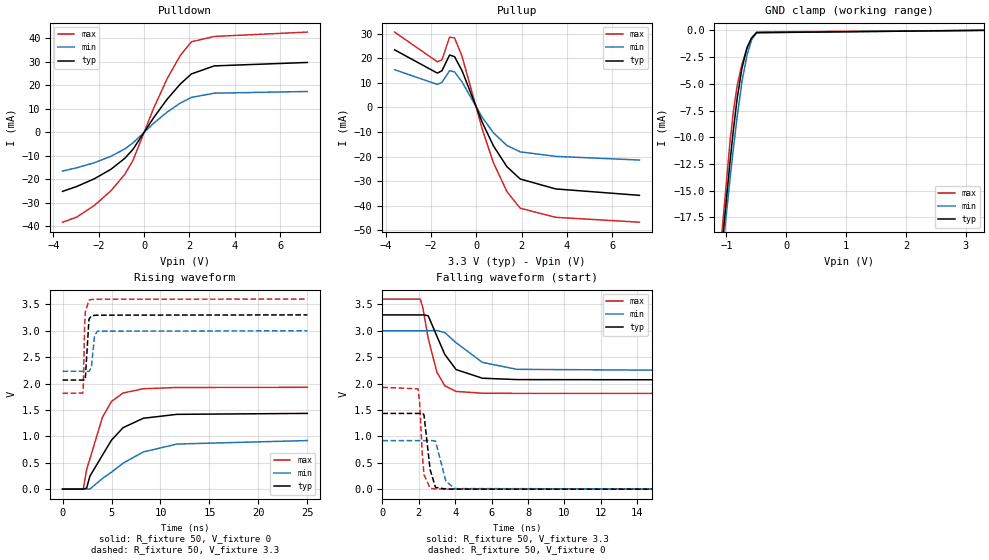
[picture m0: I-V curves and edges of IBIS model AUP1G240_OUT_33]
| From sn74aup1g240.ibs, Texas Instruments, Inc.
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[Model]   AUP1G240_OUT_33
Model_type  3-state
Enable   Active-Low
Vref =   0
Rref =   1E6
Cref =   30p
Vmeas =   1.65
| variable   typ   min   max
C_comp   2.07pF   1.81pF   2.41pF
| C_pullup   3.15pF   1.95pF   4.02pF
| C_pulldown   2.43pF   2.23pF   2.95pF
| C_tri-state   2.07pF   1.81pF   2.41pF
[Temperature Range]   40   100   -40
| Ambient temperature   25   85   -40
[Voltage range]   3.3   3   3.6
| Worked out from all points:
|   slope of the pulldown table from 0 to 0.495 V, typ, clamps not added: 68.4 ohm
|   slope of the pullup table from 0 to 0.495 V, typ, clamps not added: 45.7 ohm
|   GND clamp passes 1 mA (typ) near -0.61 V on its own axis
|   rising waveform, R_fixture 50, V_fixture 0: 20-80 % time 3.15ns typ, 4.82ns min, 2.07ns max; typ from 0 V to 1.43 V
|   falling waveform, R_fixture 50, V_fixture 3.3: 20-80 % time 1.07ns typ, 1.77ns min, 721ps max; typ from 3.3 V to 2.07 V
|   rising waveform, R_fixture 50, V_fixture 3.3: 20-80 % time 155ps typ, 217ps min, 131ps max; typ from 2.07 V to 3.3 V
|   falling waveform, R_fixture 50, V_fixture 0: 20-80 % time 244ps typ, 345ps min, 189ps max; typ from 1.43 V to 0 V
[GND Clamp]
| AUP1G240_OUT_33
|   Voltage   I(typ)   I(min)   I(max)
-3.6V     -193.5mA   -179.8mA   -210.3mA
-1.125V   -23.21mA   -23.99mA   -22.31mA
-1.1V     -21.68mA   -22.59mA   -20.6mA
-1.075V   -20.16mA   -21.2mA    -18.91mA
-940mV    -12.31mA   -13.93mA   -10.42mA
-885mV    -9.392mA   -11.14mA   -7.651mA
-820mV    -6.352mA   -8.056mA   -5.152mA
-740mV    -3.533mA   -4.797mA   -3.135mA
-655mV    -1.602mA   -2.3mA     -1.69mA
-580mV    -733.4uA   -905.1uA   -734uA
-495mV    -220.6uA   -215.1uA   -155.7uA
3.3V      272.7pA    1.972nA    65.76pA
[Pulldown]
| AUP1G240_OUT_33
|   Voltage   I(typ)   I(min)   I(max)
-3.6V     -25.22mA   -16.54mA   -38.34mA
-2.985V   -23.17mA   -15.19mA   -36.23mA
-2.205V   -19.89mA   -13.04mA   -31.29mA
-1.46V    -15.76mA   -10.26mA   -24.93mA
-855mV    -11.15mA   -7.128mA   -17.97mA
-490mV    -7.269mA   -4.538mA   -11.95mA
415mV     6.109mA    3.748mA    10.09mA
1.015V    14.06mA    8.579mA    22.82mA
1.6V      20.58mA    12.45mA    32.78mA
2.085V    24.83mA    14.83mA    38.52mA
3.09V     28.26mA    16.63mA    40.81mA
7.2V      29.73mA    17.36mA    42.67mA
[Pullup]
| AUP1G240_OUT_33
|   Voltage   I(typ)   I(min)   I(max)
-3.6V     23.4mA     15.31mA    30.62mA
-1.715V   13.93mA    9.327mA    18.54mA
-1.51V    14.91mA    10.2mA     19.34mA
-1.175V   21.28mA    14.91mA    28.58mA
-955mV    20.62mA    14.4mA     28.23mA
-625mV    14.91mA    10.34mA    20.78mA
270mV     -6.183mA   -4.136mA   -9mA
765mV     -15.76mA   -10.39mA   -22.64mA
1.355V    -24.14mA   -15.52mA   -34.29mA
1.94V     -29.14mA   -18.1mA    -41.04mA
3.505V    -33.19mA   -19.94mA   -44.73mA
7.2V      -35.8mA    -21.44mA   -46.72mA
[Ramp]
| AUP1G240_OUT_33
| variable   typ   min   max
dV/dt_r   0.86/3.15E-09   0.55/4.84E-09   1.16/2.07E-09
dV/dt_f   0.75/1.08E-09   0.47/1.78E-09   1.08/7.24E-10
R_load = 50
[Rising Waveform]
| AUP1G240_OUT_33
R_fixture =   50
C_fixture =   0
L_fixture =   0
V_fixture =   0
V_fixture_min = 0
V_fixture_max = 0
|   Time   V(typ)   V(min)   V(max)
0s        12.11nV    31.97nV    1.283nV
2.12ns    160.7uV    -11.23uV   -1.498mV
2.46ns    17.83mV    142.5uV    371.8mV
2.79ns    243mV      357.5uV    569mV
4.08ns    644.3mV    201.4mV    1.363V
5ns       927.7mV    319.8mV    1.661V
6.185ns   1.164V     491.3mV    1.821V
8.25ns    1.342V     703.7mV    1.901V
11.68ns   1.416V     853.6mV    1.925V
24.99ns   1.434V     919.3mV    1.928V
[Falling Waveform]
| AUP1G240_OUT_33
R_fixture =   50
C_fixture =   0
L_fixture =   0
V_fixture =   3.3
V_fixture_min = 3
V_fixture_max = 3.6
|   Time   V(typ)   V(min)   V(max)
0s        3.3V       3V         3.6V
2.085ns   3.3V       3V         3.6V
2.23ns    3.3V       3V         3.425V
2.515ns   3.286V     3V         2.861V
2.995ns   2.897V     3.004V     2.213V
3.43ns    2.551V     2.965V     1.958V
4.05ns    2.264V     2.772V     1.851V
5.495ns   2.101V     2.401V     1.817V
7.395ns   2.075V     2.269V     1.814V
24.99ns   2.067V     2.233V     1.814V
[Rising Waveform]
| AUP1G240_OUT_33
R_fixture =   50
C_fixture =   0
L_fixture =   0
V_fixture =   3.3
V_fixture_min = 3
V_fixture_max = 3.6
|   Time   V(typ)   V(min)   V(max)
0s        2.066V     2.232V     1.814V
2.065ns   2.066V     2.232V     1.82V
2.13ns    2.066V     2.232V     1.972V
2.245ns   2.066V     2.232V     2.998V
2.32ns    2.075V     2.232V     3.352V
2.7ns     3.217V     2.229V     3.581V
2.945ns   3.282V     2.3V       3.591V
3.27ns    3.291V     2.908V     3.596V
3.57ns    3.295V     2.991V     3.597V
24.99ns   3.3V       3V         3.6V
[Falling Waveform]
| AUP1G240_OUT_33
R_fixture =   50
C_fixture =   0
L_fixture =   0
V_fixture =   0
V_fixture_min = 0
V_fixture_max = 0
|   Time   V(typ)   V(min)   V(max)
0s        1.434V     920.1mV    1.928V
1.955ns   1.434V     920mV      1.901V
2.04ns    1.435V     920mV      1.679V
2.195ns   1.439V     919.7mV    652.9mV
2.285ns   1.408V     919.7mV    277.9mV
2.625ns   367.3mV    924mV      15.16mV
2.92ns    32.66mV    909.6mV    4.237mV
3.485ns   3.52mV     152.2mV    822.1uV
3.98ns    1.124mV    10.98mV    248.8uV
24.99ns   26.42nV    83.74nV    6.095nV
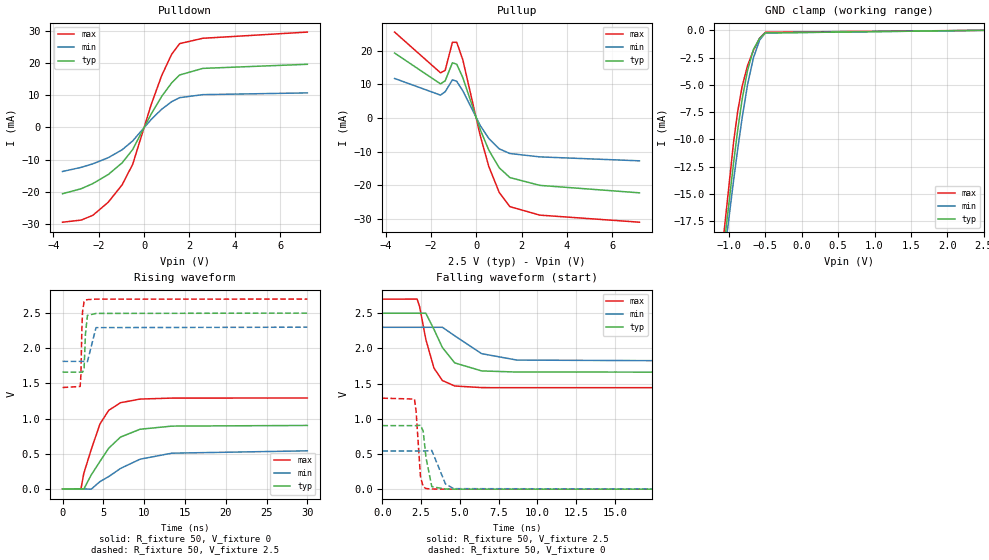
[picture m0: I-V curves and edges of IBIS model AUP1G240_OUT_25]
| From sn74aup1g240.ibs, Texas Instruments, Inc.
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[Model]   AUP1G240_OUT_25
Model_type  3-state
Enable   Active-Low
Vref =   0
Rref =   1E6
Cref =   30p
Vmeas =   1.25
| variable   typ   min   max
C_comp   2.12pF   1.87pF   2.42pF
| C_pullup   3.16pF   2.01pF   4.05pF
| C_pulldown   2.52pF   2.24pF   3.06pF
| C_tri-state   2.12pF   1.87pF   2.42pF
[Temperature Range]   40   100   -40
| Ambient temperature   25   85   -40
[Voltage range]   2.5   2.3   2.7
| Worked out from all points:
|   slope of the pulldown table from 0 to 0.375 V, typ, clamps not added: 75.2 ohm
|   slope of the pullup table from 0 to 0.375 V, typ, clamps not added: 55.1 ohm
|   GND clamp passes 1 mA (typ) near -0.61 V on its own axis
|   rising waveform, R_fixture 50, V_fixture 0: 20-80 % time 3.54ns typ, 5.12ns min, 2.39ns max; typ from 0 V to 0.903 V
|   falling waveform, R_fixture 50, V_fixture 2.5: 20-80 % time 1.27ns typ, 2.05ns min, 857ps max; typ from 2.5 V to 1.66 V
|   rising waveform, R_fixture 50, V_fixture 2.5: 20-80 % time 175ps typ, 253ps min, 147ps max; typ from 1.66 V to 2.5 V
|   falling waveform, R_fixture 50, V_fixture 0: 20-80 % time 273ps typ, 387ps min, 217ps max; typ from 0.903 V to 0 V
[GND Clamp]
| AUP1G240_OUT_25
|   Voltage   I(typ)   I(min)   I(max)
-3.6V     -193.5mA   -179.8mA   -210.3mA
-1.13V    -23.52mA   -24.27mA   -22.66mA
-1.105V   -21.99mA   -22.87mA   -20.94mA
-1.08V    -20.47mA   -21.48mA   -19.25mA
-935mV    -12.04mA   -13.67mA   -10.14mA
-880mV    -9.14mA    -10.89mA   -7.431mA
-820mV    -6.352mA   -8.056mA   -5.152mA
-745mV    -3.68mA    -4.977mA   -3.233mA
-665mV    -1.77mA    -2.542mA   -1.842mA
-580mV    -733.4uA   -905.1uA   -734uA
-500mV    -240.6uA   -235.8uA   -174.4uA
2.5V      210.4pA    1.91nA     47.26pA
[Pulldown]
| AUP1G240_OUT_25
|   Voltage   I(typ)   I(min)   I(max)
-3.6V     -20.57mA   -13.67mA   -29.41mA
-2.78V    -19.03mA   -12.39mA   -28.76mA
-2.265V   -17.43mA   -11.3mA    -27.29mA
-1.58V    -14.6mA    -9.373mA   -23.19mA
-970mV    -10.98mA   -6.922mA   -17.8mA
-505mV    -6.845mA   -4.179mA   -11.45mA
310mV     4.162mA    2.467mA    7.071mA
775mV     9.655mA    5.67mA     16.13mA
1.215V    13.84mA    8.012mA    22.73mA
1.565V    16.29mA    9.252mA    26.03mA
2.59V     18.34mA    10.19mA    27.69mA
7.2V      19.61mA    10.73mA    29.61mA
[Pullup]
| AUP1G240_OUT_25
|   Voltage   I(typ)   I(min)   I(max)
-3.6V     19.35mA    11.79mA    25.58mA
-1.575V   10.18mA    6.835mA    13.47mA
-1.37V    11.08mA    7.836mA    14.2mA
-1.05V    16.45mA    11.37mA    22.53mA
-860mV    16.03mA    10.95mA    22.55mA
-590mV    12.03mA    8.106mA    17.31mA
180mV     -3.459mA   -2.233mA   -5.283mA
555mV     -9.511mA   -6.049mA   -14.36mA
1.015V    -14.77mA   -9.13mA    -22.1mA
1.485V    -17.68mA   -10.53mA   -26.32mA
2.805V    -20mA      -11.53mA   -28.85mA
7.2V      -22.22mA   -12.7mA    -30.95mA
[Ramp]
| AUP1G240_OUT_25
| variable   typ   min   max
dV/dt_r   0.54/3.56E-09   0.33/5.17E-09   0.78/2.39E-09
dV/dt_f   0.51/1.27E-09   0.30/2.06E-09   0.76/8.61E-10
R_load = 50
[Rising Waveform]
| AUP1G240_OUT_25
R_fixture =   50
C_fixture =   0
L_fixture =   0
V_fixture =   0
V_fixture_min = 0
V_fixture_max = 0
|   Time   V(typ)   V(min)   V(max)
0s        8.96nV     28.07nV    865.3pV
2.265ns   58.37uV    -8.263uV   1.77mV
2.605ns   -2.543mV   -1.172uV   222.1mV
3.515ns   198.6mV    -3.157mV   559.5mV
4.585ns   391mV      104.2mV    923.9mV
5.665ns   580mV      176.4mV    1.118V
7.1ns     737.4mV    291.3mV    1.226V
9.5ns     848.9mV    423.2mV    1.278V
13.39ns   893.5mV    508.6mV    1.292V
29.99ns   902.9mV    541.9mV    1.293V
[Falling Waveform]
| AUP1G240_OUT_25
R_fixture =   50
C_fixture =   0
L_fixture =   0
V_fixture =   2.5
V_fixture_min = 2.3
V_fixture_max = 2.7
|   Time   V(typ)   V(min)   V(max)
0s        2.5V       2.3V       2.7V
2.24ns    2.5V       2.3V       2.701V
2.405ns   2.499V     2.3V       2.592V
2.805ns   2.499V     2.3V       2.128V
3.33ns    2.271V     2.3V       1.72V
3.875ns   2.012V     2.3V       1.543V
4.67ns    1.794V     2.179V     1.466V
6.41ns    1.68V      1.925V     1.443V
8.69ns    1.664V     1.834V     1.442V
29.99ns   1.662V     1.814V     1.442V
[Rising Waveform]
| AUP1G240_OUT_25
R_fixture =   50
C_fixture =   0
L_fixture =   0
V_fixture =   2.5
V_fixture_min = 2.3
V_fixture_max = 2.7
|   Time   V(typ)   V(min)   V(max)
0s        1.661V     1.814V     1.442V
2.16ns    1.661V     1.814V     1.457V
2.255ns   1.661V     1.814V     1.622V
2.37ns    1.66V      1.814V     2.273V
2.45ns    1.659V     1.814V     2.518V
2.64ns    1.703V     1.814V     2.662V
2.81ns    2.204V     1.814V     2.686V
3.05ns    2.467V     1.811V     2.692V
4.105ns   2.496V     2.294V     2.699V
29.99ns   2.5V       2.3V       2.7V
[Falling Waveform]
| AUP1G240_OUT_25
R_fixture =   50
C_fixture =   0
L_fixture =   0
V_fixture =   0
V_fixture_min = 0
V_fixture_max = 0
|   Time   V(typ)   V(min)   V(max)
0s        902.9mV    542.1mV    1.293V
2.07ns    902.6mV    542.1mV    1.28V
2.175ns   903mV      542mV      1.114V
2.46ns    908.1mV    541.7mV    174.9mV
2.635ns   825.7mV    541.7mV    34.71mV
2.815ns   447.7mV    542.5mV    8.342mV
3.19ns    35.55mV    550.1mV    2.449mV
4.07ns    1.667mV    75.73mV    264.9uV
4.6ns     593.9uV    7.206mV    91.14uV
29.99ns   35.6nV     66.32nV    6.812nV
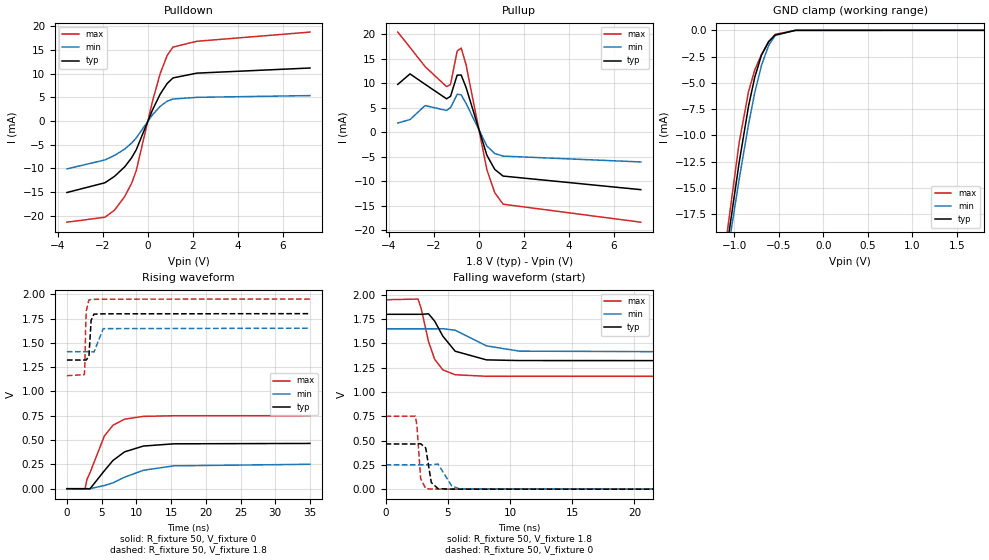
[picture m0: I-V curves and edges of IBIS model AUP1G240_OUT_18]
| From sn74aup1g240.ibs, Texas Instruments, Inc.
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[Model]   AUP1G240_OUT_18
Model_type  3-state
Enable   Active-Low
Vref =   0
Rref =   1E6
Cref =   30p
Vmeas =   0.9
| variable   typ   min   max
C_comp   2.18pF   1.95pF   2.43pF
| C_pullup   3.13pF   2.07pF   4.02pF
| C_pulldown   2.62pF   2.25pF   3.11pF
| C_tri-state   2.18pF   1.95pF   2.43pF
[Temperature Range]   40   100   -40
| Ambient temperature   25   85   -40
[Voltage range]   1.8   1.65   1.95
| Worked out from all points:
|   slope of the pulldown table from 0 to 0.27 V, typ, clamps not added: 88.7 ohm
|   slope of the pullup table from 0 to 0.27 V, typ, clamps not added: 73.8 ohm
|   GND clamp passes 1 mA (typ) near -0.61 V on its own axis
|   rising waveform, R_fixture 50, V_fixture 0: 20-80 % time 3.87ns typ, 5.45ns min, 2.72ns max; typ from 0 V to 0.465 V
|   falling waveform, R_fixture 50, V_fixture 1.8: 20-80 % time 1.55ns typ, 2.45ns min, 1.04ns max; typ from 1.8 V to 1.32 V
|   rising waveform, R_fixture 50, V_fixture 1.8: 20-80 % time 225ps typ, 296ps min, 160ps max; typ from 1.32 V to 1.8 V
|   falling waveform, R_fixture 50, V_fixture 0: 20-80 % time 323ps typ, 464ps min, 230ps max; typ from 0.465 V to 0 V
[GND Clamp]
| AUP1G240_OUT_18
|   Voltage   I(typ)   I(min)   I(max)
-3.6V     -193.5mA   -179.8mA   -210.3mA
-1.145V   -24.45mA   -25.12mA   -23.69mA
-1.12V    -22.91mA   -23.71mA   -21.97mA
-1.095V   -21.38mA   -22.31mA   -20.26mA
-945mV    -12.59mA   -14.19mA   -10.7mA
-840mV    -7.225mA   -8.974mA   -5.843mA
-770mV    -4.469mA   -5.928mA   -3.764mA
-695mV    -2.373mA   -3.346mA   -2.326mA
-615mV    -1.069mA   -1.463mA   -1.136mA
-540mV    -445.1uA   -477.4uA   -389.8uA
-315mV    -2.831uA   -4.163uA   -587.7nA
1.8V      163.6pA    2.099nA    32.78pA
[Pulldown]
| AUP1G240_OUT_18
|   Voltage   I(typ)   I(min)   I(max)
-3.6V     -15.12mA   -10.13mA   -21.39mA
-1.91V    -13.06mA   -8.236mA   -20.34mA
-1.485V   -11.71mA   -7.301mA   -18.84mA
-1.03V    -9.681mA   -5.933mA   -15.95mA
-725mV    -7.787mA   -4.683mA   -13.18mA
-520mV    -6.099mA   -3.59mA    -10.49mA
205mV     2.352mA    1.308mA    4.202mA
545mV     5.664mA    3.086mA    10.01mA
855mV     7.912mA    4.18mA     13.84mA
1.115V    9.087mA    4.628mA    15.61mA
2.18V     10.1mA     4.986mA    16.83mA
7.2V      11.18mA    5.355mA    18.77mA
[Pullup]
| AUP1G240_OUT_18
|   Voltage   I(typ)   I(min)   I(max)
-3.6V     9.764mA    1.888mA    20.42mA
-3.055V   11.9mA     2.599mA    17.29mA
-2.385V   9.785mA    5.444mA    13.38mA
-1.43V    6.82mA     4.441mA    9.299mA
-1.255V   7.335mA    5.04mA     9.735mA
-960mV    11.65mA    7.76mA     16.56mA
-780mV    11.66mA    7.635mA    17.16mA
-565mV    9.148mA    5.886mA    13.78mA
360mV     -4.671mA   -2.782mA   -7.616mA
710mV     -7.556mA   -4.323mA   -12.3mA
1.08V     -8.919mA   -4.855mA   -14.65mA
7.2V      -11.69mA   -6.041mA   -18.32mA
[Ramp]
| AUP1G240_OUT_18
| variable   typ   min   max
dV/dt_r   0.28/3.91E-09   0.15/5.57E-09   0.45/2.74E-09
dV/dt_f   0.29/1.56E-09   0.15/2.47E-09   0.48/1.04E-09
R_load = 50
[Rising Waveform]
| AUP1G240_OUT_18
R_fixture =   50
C_fixture =   0
L_fixture =   0
V_fixture =   0
V_fixture_min = 0
V_fixture_max = 0
|   Time   V(typ)   V(min)   V(max)
0s        6.973nV    25.31nV    613.1pV
2.6ns     2.172uV    -5.915uV   -4.821mV
2.89ns    390.8uV    -12.12uV   96.14mV
3.305ns   -2.687mV   5.918uV    161.3mV
5.385ns   184.2mV    32.48mV    541.1mV
6.64ns    290.8mV    60.66mV    653mV
8.3ns     378.8mV    118.1mV    714.9mV
11ns      438.6mV    189.3mV    743.5mV
15.4ns    461.5mV    235.1mV    750.3mV
34.99ns   465.4mV    251mV      750.9mV
[Falling Waveform]
| AUP1G240_OUT_18
R_fixture =   50
C_fixture =   0
L_fixture =   0
V_fixture =   1.8
V_fixture_min = 1.65
V_fixture_max = 1.95
|   Time   V(typ)   V(min)   V(max)
0s        1.8V       1.65V      1.95V
2.605ns   1.8V       1.65V      1.957V
2.85ns    1.8V       1.65V      1.864V
3.45ns    1.805V     1.65V      1.519V
3.94ns    1.73V      1.65V      1.337V
4.6ns     1.575V     1.652V     1.228V
5.59ns    1.42V      1.636V     1.178V
8.105ns   1.331V     1.475V     1.162V
10.74ns   1.324V     1.421V     1.162V
34.99ns   1.323V     1.409V     1.162V
[Rising Waveform]
| AUP1G240_OUT_18
R_fixture =   50
C_fixture =   0
L_fixture =   0
V_fixture =   1.8
V_fixture_min = 1.65
V_fixture_max = 1.95
|   Time   V(typ)   V(min)   V(max)
0s        1.323V     1.409V     1.162V
2.5ns     1.323V     1.409V     1.173V
2.575ns   1.323V     1.409V     1.25V
2.7ns     1.323V     1.409V     1.669V
2.785ns   1.323V     1.409V     1.827V
3.17ns    1.363V     1.41V      1.941V
3.485ns   1.732V     1.409V     1.945V
3.895ns   1.795V     1.406V     1.947V
5.23ns    1.798V     1.646V     1.949V
34.99ns   1.8V       1.65V      1.95V
[Falling Waveform]
| AUP1G240_OUT_18
R_fixture =   50
C_fixture =   0
L_fixture =   0
V_fixture =   0
V_fixture_min = 0
V_fixture_max = 0
|   Time   V(typ)   V(min)   V(max)
0s        465.4mV    251mV      750.9mV
2.4ns     465.1mV    251mV      751.2mV
2.52ns    465.1mV    251mV      647.6mV
2.815ns   467.9mV    250.8mV    109.6mV
3.225ns   423.7mV    250.7mV    5.276mV
3.67ns    68.64mV    251.4mV    1.553mV
4.215ns   4.768mV    258.5mV    408.8uV
5.29ns    586uV      36.24mV    53.52uV
5.9ns     250.2uV    4.43mV     20.2uV
34.99ns   22.05nV    71.19nV    12.74nV
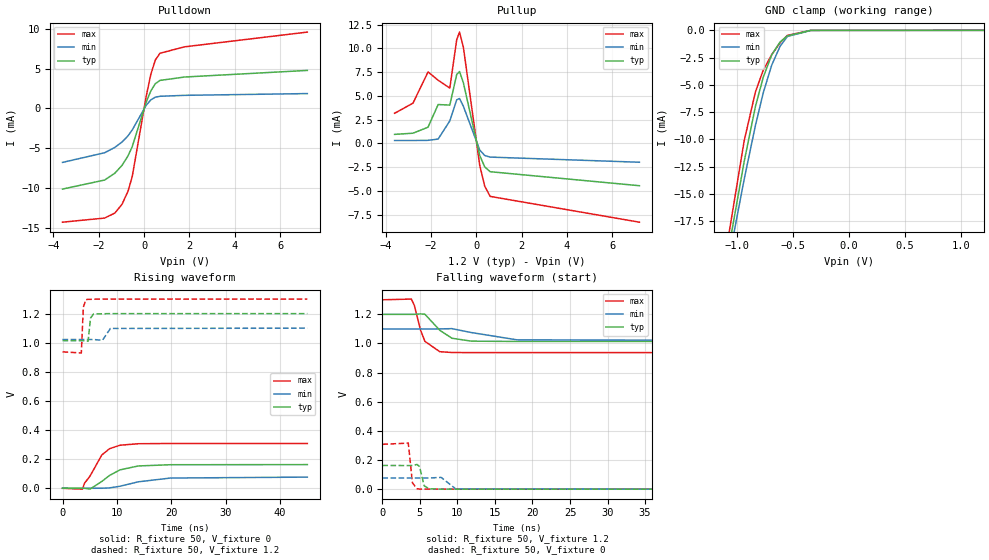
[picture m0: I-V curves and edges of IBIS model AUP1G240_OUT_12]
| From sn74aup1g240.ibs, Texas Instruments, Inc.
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[Model]   AUP1G240_OUT_12
Model_type  3-state
Enable   Active-Low
Vref =   0
Rref =   1E6
Cref =   30p
Vmeas =   0.6
| variable   typ   min   max
C_comp   2.26pF   2.06pF   2.47pF
| C_pullup   3.02pF   2.17pF   3.84pF
| C_pulldown   2.69pF   2.26pF   3.19pF
| C_tri-state   2.26pF   2.06pF   2.47pF
[Temperature Range]   40   100   -40
| Ambient temperature   25   85   -40
[Voltage range]   1.2   1.1   1.3
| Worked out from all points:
|   slope of the pulldown table from 0 to 0.18 V, typ, clamps not added: 125 ohm
|   slope of the pullup table from 0 to 0.18 V, typ, clamps not added: 123 ohm
|   GND clamp passes 1 mA (typ) near -0.61 V on its own axis
|   rising waveform, R_fixture 50, V_fixture 0: 20-80 % time 4.2ns typ, 5.97ns min, 3ns max; typ from 0 V to 0.163 V
|   falling waveform, R_fixture 50, V_fixture 1.2: 20-80 % time 2ns typ, 3.36ns min, 1.28ns max; typ from 1.2 V to 1.01 V
|   rising waveform, R_fixture 50, V_fixture 1.2: 20-80 % time 264ps typ, 390ps min, 212ps max; typ from 1.01 V to 1.2 V
|   falling waveform, R_fixture 50, V_fixture 0: 20-80 % time 416ps typ, 661ps min, 299ps max; typ from 0.163 V to 0 V
[GND Clamp]
| AUP1G240_OUT_12
|   Voltage   I(typ)   I(min)   I(max)
-3.6V     -193.5mA   -179.8mA   -210.3mA
-1.12V    -22.91mA   -23.71mA   -21.97mA
-1.1V     -21.68mA   -22.59mA   -20.6mA
-1.08V    -20.47mA   -21.48mA   -19.25mA
-935mV    -12.04mA   -13.67mA   -10.14mA
-835mV    -7.001mA   -8.742mA   -5.664mA
-765mV    -4.304mA   -5.731mA   -3.651mA
-690mV    -2.262mA   -3.204mA   -2.243mA
-615mV    -1.069mA   -1.463mA   -1.136mA
-550mV    -509.1uA   -564.4uA   -463.6uA
-340mV    -5.773uA   -7.67uA    -1.491uA
1.2V      128.4pA    3.511nA    21.35pA
[Pulldown]
| AUP1G240_OUT_12
|   Voltage   I(typ)   I(min)   I(max)
-3.6V     -10.14mA   -6.792mA   -14.3mA
-1.74V    -9.004mA   -5.576mA   -13.78mA
-1.29V    -8.143mA   -4.904mA   -13.15mA
-975mV    -7.165mA   -4.229mA   -12.05mA
-710mV    -5.969mA   -3.453mA   -10.41mA
-525mV    -4.815mA   -2.713mA   -8.581mA
90mV      761.5uA    381.6uA    1.487mA
295mV     2.185mA    1.055mA    4.264mA
495mV     3.092mA    1.407mA    6.07mA
700mV     3.505mA    1.511mA    6.919mA
1.785V    3.931mA    1.63mA     7.723mA
7.2V      4.761mA    1.852mA    9.574mA
[Pullup]
| AUP1G240_OUT_12
|   Voltage   I(typ)   I(min)   I(max)
-3.6V     938.3uA    292.3uA    3.161mA
-2.79V    1.061mA    291.5uA    4.222mA
-2.125V   1.693mA    310.3uA    7.513mA
-1.68V    4.08mA     442.8uA    6.642mA
-1.165V   4.022mA    2.354mA    5.813mA
-860mV    7.245mA    4.579mA    10.91mA
-735mV    7.558mA    4.716mA    11.71mA
-565mV    6.361mA    3.892mA    10.1mA
155mV     -1.288mA   -703.8uA   -2.322mA
375mV     -2.48mA    -1.288mA   -4.509mA
615mV     -2.993mA   -1.455mA   -5.593mA
7.2V      -4.468mA   -1.996mA   -8.31mA
[Ramp]
| AUP1G240_OUT_12
| variable   typ   min   max
dV/dt_r   0.10/4.36E-09   0.05/6.31E-09   0.19/3.08E-09
dV/dt_f   0.11/2.02E-09   0.05/3.40E-09   0.22/1.29E-09
R_load = 50
[Rising Waveform]
| AUP1G240_OUT_12
R_fixture =   50
C_fixture =   0
L_fixture =   0
V_fixture =   0
V_fixture_min = 0
V_fixture_max = 0
|   Time   V(typ)   V(min)   V(max)
0s        5.831nV    23.96nV    441.9pV
3.655ns   -5.062uV   -3.023uV   -6.13mV
4.035ns   84.64uV    -4.062uV   34.1mV
5.055ns   -5.651mV   -4.725uV   83.88mV
7.205ns   46.45mV    158.7uV    228mV
8.645ns   88.15mV    2.634mV    272.1mV
10.57ns   126.6mV    13.9mV     295.8mV
13.92ns   153.3mV    44.33mV    306mV
19.83ns   161.8mV    70.3mV     307.8mV
45ns      162.6mV    76.67mV    307.8mV
[Falling Waveform]
| AUP1G240_OUT_12
R_fixture =   50
C_fixture =   0
L_fixture =   0
V_fixture =   1.2
V_fixture_min = 1.1
V_fixture_max = 1.3
|   Time   V(typ)   V(min)   V(max)
0s        1.2V       1.1V       1.3V
3.86ns    1.2V       1.1V       1.305V
4.26ns    1.2V       1.1V       1.262V
5.08ns    1.203V     1.1V       1.093V
5.665ns   1.201V     1.1V       1.015V
7.645ns   1.091V     1.1V       943.8mV
9.27ns    1.036V     1.102V     938.2mV
11.88ns   1.016V     1.075V     937.4mV
17.94ns   1.014V     1.025V     937.4mV
45ns      1.014V     1.022V     937.4mV
[Rising Waveform]
| AUP1G240_OUT_12
R_fixture =   50
C_fixture =   0
L_fixture =   0
V_fixture =   1.2
V_fixture_min = 1.1
V_fixture_max = 1.3
|   Time   V(typ)   V(min)   V(max)
0s        1.014V     1.022V     937.3mV
3.455ns   1.014V     1.022V     929.7mV
3.83ns    1.014V     1.022V     1.245V
4.305ns   1.011V     1.022V     1.296V
4.705ns   1.011V     1.022V     1.298V
5.145ns   1.169V     1.022V     1.298V
5.69ns    1.197V     1.022V     1.299V
7.34ns    1.199V     1.017V     1.3V
8.81ns    1.2V       1.098V     1.3V
45ns      1.2V       1.1V       1.3V
[Falling Waveform]
| AUP1G240_OUT_12
R_fixture =   50
C_fixture =   0
L_fixture =   0
V_fixture =   0
V_fixture_min = 0
V_fixture_max = 0
|   Time   V(typ)   V(min)   V(max)
0s        162.6mV    76.67mV    307.8mV
3.455ns   162.3mV    76.66mV    316.3mV
4.005ns   162.6mV    76.6mV     43.33mV
4.615ns   169.6mV    76.56mV    2.499mV
4.955ns   155.2mV    76.53mV    1.117mV
5.57ns    23.01mV    76.47mV    332.8uV
6.225ns   2.72mV     76.79mV    112.6uV
7.83ns    381.9uV    80.79mV    11.91uV
9.78ns    59.08uV    1.813mV    985.4nV
45ns      55.26nV    97.5nV     26.01nV
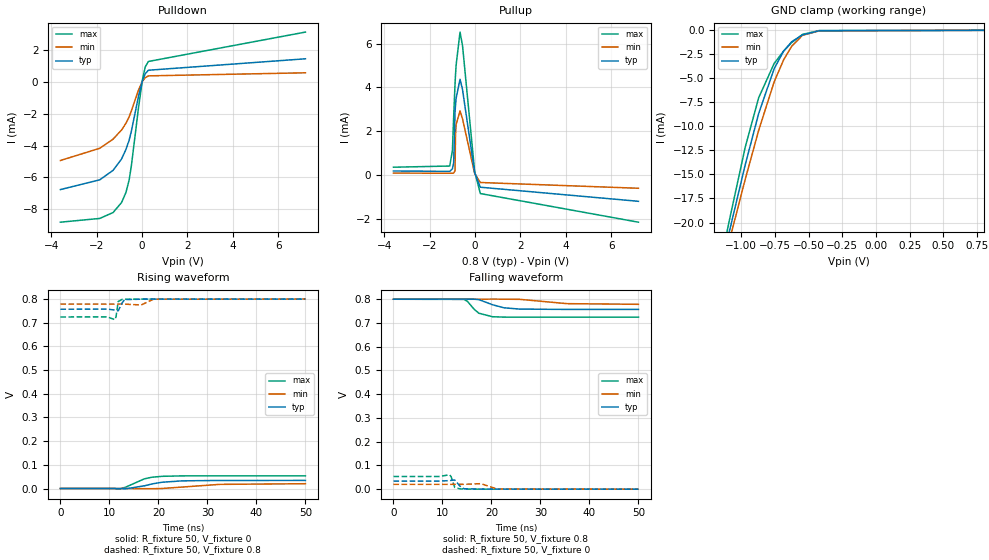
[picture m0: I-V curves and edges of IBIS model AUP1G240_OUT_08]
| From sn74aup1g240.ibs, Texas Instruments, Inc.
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[Model]   AUP1G240_OUT_08
Model_type  3-state
Enable   Active-Low
Vref =   0
Rref =   1E6
Cref =   30p
Vmeas =   0.4
| variable   typ   min   max
C_comp   2.32pF   2.11pF   2.51pF
| C_pullup   2.78pF   2.25pF   3.33pF
| C_pulldown   2.66pF   2.23pF   3.12pF
| C_tri-state   2.32pF   2.11pF   2.51pF
[Temperature Range]   40   100   -40
| Ambient temperature   25   85   -40
[Voltage range]   0.8   0.8   0.8
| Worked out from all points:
|   slope of the pulldown table from 0 to 0.12 V, typ, clamps not added: 257 ohm
|   slope of the pullup table from 0 to 0.12 V, typ, clamps not added: 302 ohm
|   GND clamp passes 1 mA (typ) near -0.61 V on its own axis
[GND Clamp]
| AUP1G240_OUT_08
|   Voltage   I(typ)   I(min)   I(max)
-3.6V     -193.5mA   -179.8mA   -210.3mA
-1.13V    -23.52mA   -24.27mA   -22.66mA
-1.11V    -22.29mA   -23.15mA   -21.28mA
-1.09V    -21.07mA   -22.03mA   -19.92mA
-970mV    -13.99mA   -15.5mA    -12.16mA
-870mV    -8.642mA   -10.4mA    -7.008mA
-755mV    -3.985mA   -5.347mA   -3.436mA
-685mV    -2.156mA   -3.064mA   -2.16mA
-625mV    -1.184mA   -1.653mA   -1.265mA
-545mV    -476.4uA   -519.4uA   -425.6uA
-420mV    -46.16uA   -47.99uA   -21.13uA
800mV     106.9pA    551.1pA    15.87pA
[Pulldown]
| AUP1G240_OUT_08
|   Voltage   I(typ)   I(min)   I(max)
-3.6V     -6.763mA   -4.935mA   -8.814mA
-1.865V   -6.15mA    -4.166mA   -8.578mA
-1.28V    -5.555mA   -3.595mA   -8.209mA
-905mV    -4.84mA    -3.018mA   -7.581mA
-710mV    -4.24mA    -2.594mA   -6.943mA
-570mV    -3.655mA   -2.186mA   -6.156mA
-470mV    -3.08mA    -1.812mA   -5.243mA
-155mV    -882uA     -491.6uA   -1.594mA
15mV      70.31uA    36.95uA    134.1uA
140mV     523.3uA    274.6uA    953.9uA
280mV     740uA      385.5uA    1.291mA
7.2V      1.459mA    578.6uA    3.138mA
[Pullup]
| AUP1G240_OUT_08
|   Voltage   I(typ)   I(min)   I(max)
-3.6V     173.2uA    77.31uA    346.4uA
-1.12V    155.8uA    71.47uA    400.2uA
-1V       271.5uA    72.31uA    1.109mA
-945mV    558.4uA    80.56uA    2.665mA
-885mV    2.856mA    183.3uA    4.162mA
-865mV    3.17mA     1.755mA    4.547mA
-840mV    3.485mA    2.289mA    4.99mA
-665mV    4.366mA    2.921mA    6.526mA
-555mV    3.897mA    2.556mA    5.908mA
-20mV     90.78uA    56.3uA     147uA
230mV     -568.5uA   -352.9uA   -857.8uA
7.2V      -1.213mA   -616.6uA   -2.168mA
[Ramp]
| AUP1G240_OUT_08
| variable   typ   min   max
dV/dt_r   0.02/5.10E-09   0.01/7.47E-09   0.03/3.64E-09
dV/dt_f   0.03/3.52E-09   0.01/5.87E-09   0.05/2.21E-09
R_load = 50
[Rising Waveform]
| AUP1G240_OUT_08
R_fixture =   50
C_fixture =   0
L_fixture =   0
V_fixture =   0
V_fixture_min = 0
V_fixture_max = 0
|   Time   V(typ)   V(min)   V(max)
0s        5.542nV    24.01nV    351.9pV
10.95ns   134.2uV    -3.927uV   159.9uV
11.91ns   -37.64uV   -1.003uV   -2.808mV
13.32ns   -1.421mV   35.77uV    5.755mV
17.14ns   11.34mV    -726.4uV   40.8mV
18.69ns   19.2mV     -917.8uV   47.65mV
20.72ns   26.39mV    49.18uV    51.43mV
24.82ns   32.29mV    5.993mV    53.25mV
32.44ns   33.95mV    17.4mV     53.49mV
50ns      34.06mV    20.25mV    53.5mV
[Falling Waveform]
| AUP1G240_OUT_08
R_fixture =   50
C_fixture =   0
L_fixture =   0
V_fixture =   0.8
V_fixture_min = 0.8
V_fixture_max = 0.8
|   Time   V(typ)   V(min)   V(max)
0s        800mV      800mV      800mV
14.36ns   800.7mV    800mV      799.3mV
15.08ns   800.4mV    799.9mV    791.6mV
16.53ns   800mV      799.9mV    756.3mV
17.44ns   798.3mV    799.9mV    741mV
20.21ns   776.8mV    800.5mV    726.3mV
22.57ns   763.8mV    800.2mV    724.7mV
25.82ns   758.4mV    799.5mV    724.4mV
35.39ns   757.1mV    781.4mV    724.4mV
50ns      757.1mV    778.6mV    724.4mV
[Rising Waveform]
| AUP1G240_OUT_08
R_fixture =   50
C_fixture =   0
L_fixture =   0
V_fixture =   0.8
V_fixture_min = 0.8
V_fixture_max = 0.8
|   Time   V(typ)   V(min)   V(max)
0s        757.1mV    778.6mV    724.4mV
9.58ns    757.4mV    778.6mV    724.7mV
11.14ns   753.6mV    778.7mV    712.9mV
11.35ns   752.4mV    778.7mV    724.9mV
11.79ns   750mV      778.8mV    789.3mV
12.59ns   784mV      778.7mV    798.6mV
13.12ns   797.7mV    778.6mV    799.1mV
16.48ns   799.5mV    775mV      799.8mV
18.97ns   799.8mV    799.2mV    800mV
50ns      800mV      800mV      800mV
[Falling Waveform]
| AUP1G240_OUT_08
R_fixture =   50
C_fixture =   0
L_fixture =   0
V_fixture =   0
V_fixture_min = 0
V_fixture_max = 0
|   Time   V(typ)   V(min)   V(max)
0s        34.06mV    20.29mV    53.5mV
9.35ns    33.94mV    20.24mV    53.52mV
11.46ns   36.11mV    20.19mV    60.59mV
11.76ns   36.98mV    20.19mV    52.88mV
12.5ns    38.7mV     20.19mV    7.475mV
13.58ns   12.83mV    20.3mV     1.072mV
14.43ns   1.719mV    20.59mV    550.1uV
17.86ns   326.4uV    23.14mV    47.53uV
21.12ns   82.8uV     788.7uV    3.382uV
50ns      73.71nV    416.9nV    25.05nV
